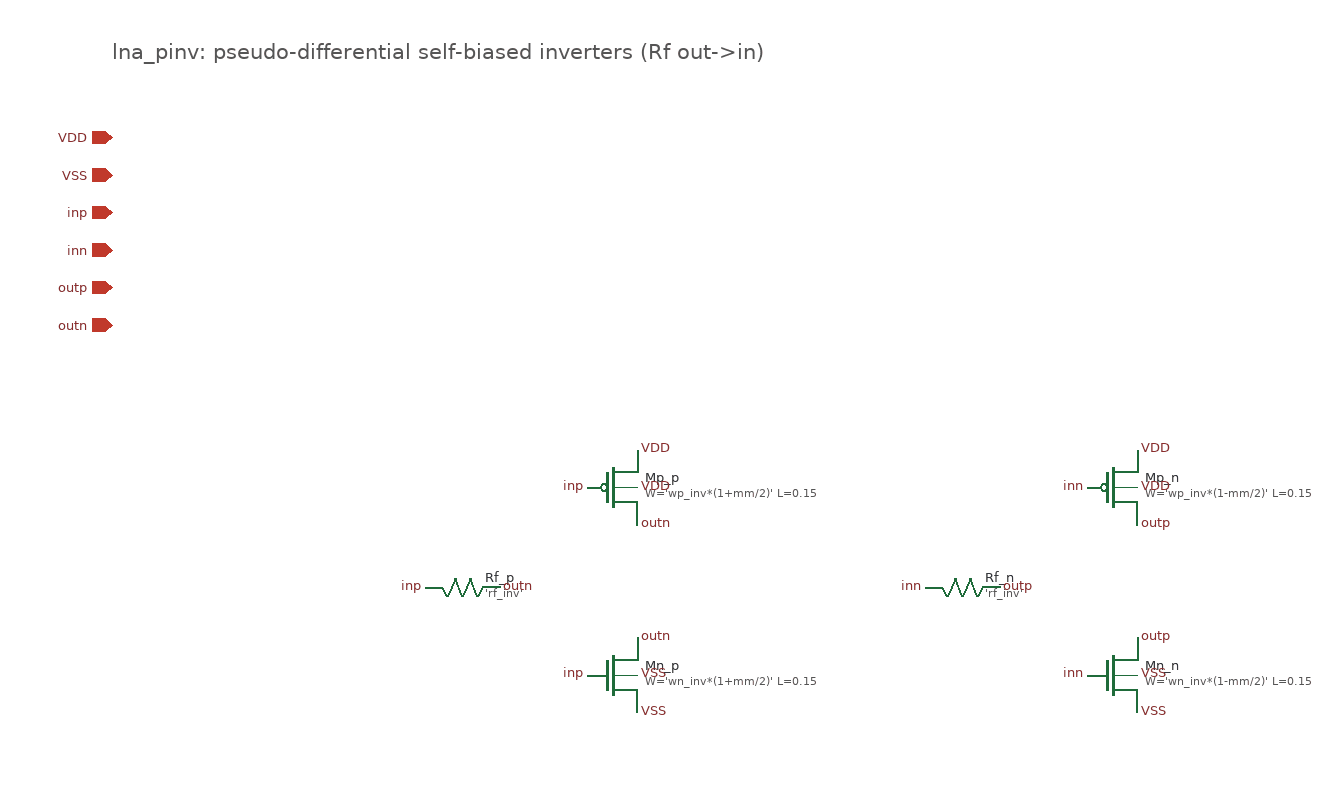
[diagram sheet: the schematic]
v {xschem version=3.4.5 file_version=1.2
}
G {}
K {}
V {}
S {}
E {}
T {lna_pinv: pseudo-differential self-biased inverters (Rf out->in)} -400 -560 0 0 0.5 0.5 {}
C {devices/iopin.sym} -400 -480 0 0 {name=p1
lab=VDD}
C {devices/iopin.sym} -400 -450 0 0 {name=p2
lab=VSS}
C {devices/iopin.sym} -400 -420 0 0 {name=p3
lab=inp}
C {devices/iopin.sym} -400 -390 0 0 {name=p4
lab=inn}
C {devices/iopin.sym} -400 -360 0 0 {name=p5
lab=outp}
C {devices/iopin.sym} -400 -330 0 0 {name=p6
lab=outn}
C {sky130_fd_pr/pfet_01v8.sym} 0 -200 0 0 {name=Mp_p
nf=8
mult=1
ad="'int((nf+1)/2) * W/nf * 0.29'"
pd="'2*int((nf+1)/2) * (W/nf + 0.29)'"
as="'int((nf+2)/2) * W/nf * 0.29'"
ps="'2*int((nf+2)/2) * (W/nf + 0.29)'"
nrd="'0.29 / W'"
nrs="'0.29 / W'"
sa=0
sb=0
sd=0
L=0.15
W='wp_inv*(1+mm/2)'
model=pfet_01v8
spiceprefix=X}
C {devices/lab_pin.sym} 20 -170 0 1 {name=p7
sig_type=std_logic
lab=outn}
C {devices/lab_pin.sym} -20 -200 0 0 {name=p8
sig_type=std_logic
lab=inp}
C {devices/lab_pin.sym} 20 -230 0 1 {name=p9
sig_type=std_logic
lab=VDD}
C {devices/lab_pin.sym} 20 -200 0 1 {name=p10
sig_type=std_logic
lab=VDD}
C {sky130_fd_pr/nfet_01v8.sym} 0 -50 0 0 {name=Mn_p
nf=4
mult=1
ad="'int((nf+1)/2) * W/nf * 0.29'"
pd="'2*int((nf+1)/2) * (W/nf + 0.29)'"
as="'int((nf+2)/2) * W/nf * 0.29'"
ps="'2*int((nf+2)/2) * (W/nf + 0.29)'"
nrd="'0.29 / W'"
nrs="'0.29 / W'"
sa=0
sb=0
sd=0
L=0.15
W='wn_inv*(1+mm/2)'
model=nfet_01v8
spiceprefix=X}
C {devices/lab_pin.sym} 20 -80 0 1 {name=p11
sig_type=std_logic
lab=outn}
C {devices/lab_pin.sym} -20 -50 0 0 {name=p12
sig_type=std_logic
lab=inp}
C {devices/lab_pin.sym} 20 -20 0 1 {name=p13
sig_type=std_logic
lab=VSS}
C {devices/lab_pin.sym} 20 -50 0 1 {name=p14
sig_type=std_logic
lab=VSS}
C {devices/res.sym} -120 -120 1 0 {name=Rf_p
value='rf_inv'
m=1}
C {devices/lab_pin.sym} -90 -120 0 1 {name=p15
sig_type=std_logic
lab=outn}
C {devices/lab_pin.sym} -150 -120 0 0 {name=p16
sig_type=std_logic
lab=inp}
C {sky130_fd_pr/pfet_01v8.sym} 400 -200 0 0 {name=Mp_n
nf=8
mult=1
ad="'int((nf+1)/2) * W/nf * 0.29'"
pd="'2*int((nf+1)/2) * (W/nf + 0.29)'"
as="'int((nf+2)/2) * W/nf * 0.29'"
ps="'2*int((nf+2)/2) * (W/nf + 0.29)'"
nrd="'0.29 / W'"
nrs="'0.29 / W'"
sa=0
sb=0
sd=0
L=0.15
W='wp_inv*(1-mm/2)'
model=pfet_01v8
spiceprefix=X}
C {devices/lab_pin.sym} 420 -170 0 1 {name=p17
sig_type=std_logic
lab=outp}
C {devices/lab_pin.sym} 380 -200 0 0 {name=p18
sig_type=std_logic
lab=inn}
C {devices/lab_pin.sym} 420 -230 0 1 {name=p19
sig_type=std_logic
lab=VDD}
C {devices/lab_pin.sym} 420 -200 0 1 {name=p20
sig_type=std_logic
lab=VDD}
C {sky130_fd_pr/nfet_01v8.sym} 400 -50 0 0 {name=Mn_n
nf=4
mult=1
ad="'int((nf+1)/2) * W/nf * 0.29'"
pd="'2*int((nf+1)/2) * (W/nf + 0.29)'"
as="'int((nf+2)/2) * W/nf * 0.29'"
ps="'2*int((nf+2)/2) * (W/nf + 0.29)'"
nrd="'0.29 / W'"
nrs="'0.29 / W'"
sa=0
sb=0
sd=0
L=0.15
W='wn_inv*(1-mm/2)'
model=nfet_01v8
spiceprefix=X}
C {devices/lab_pin.sym} 420 -80 0 1 {name=p21
sig_type=std_logic
lab=outp}
C {devices/lab_pin.sym} 380 -50 0 0 {name=p22
sig_type=std_logic
lab=inn}
C {devices/lab_pin.sym} 420 -20 0 1 {name=p23
sig_type=std_logic
lab=VSS}
C {devices/lab_pin.sym} 420 -50 0 1 {name=p24
sig_type=std_logic
lab=VSS}
C {devices/res.sym} 280 -120 1 0 {name=Rf_n
value='rf_inv'
m=1}
C {devices/lab_pin.sym} 310 -120 0 1 {name=p25
sig_type=std_logic
lab=outp}
C {devices/lab_pin.sym} 250 -120 0 0 {name=p26
sig_type=std_logic
lab=inn}
